VERSION 5.7 ;
  NOWIREEXTENSIONATPIN ON ;
  DIVIDERCHAR "/" ;
  BUSBITCHARS "[]" ;
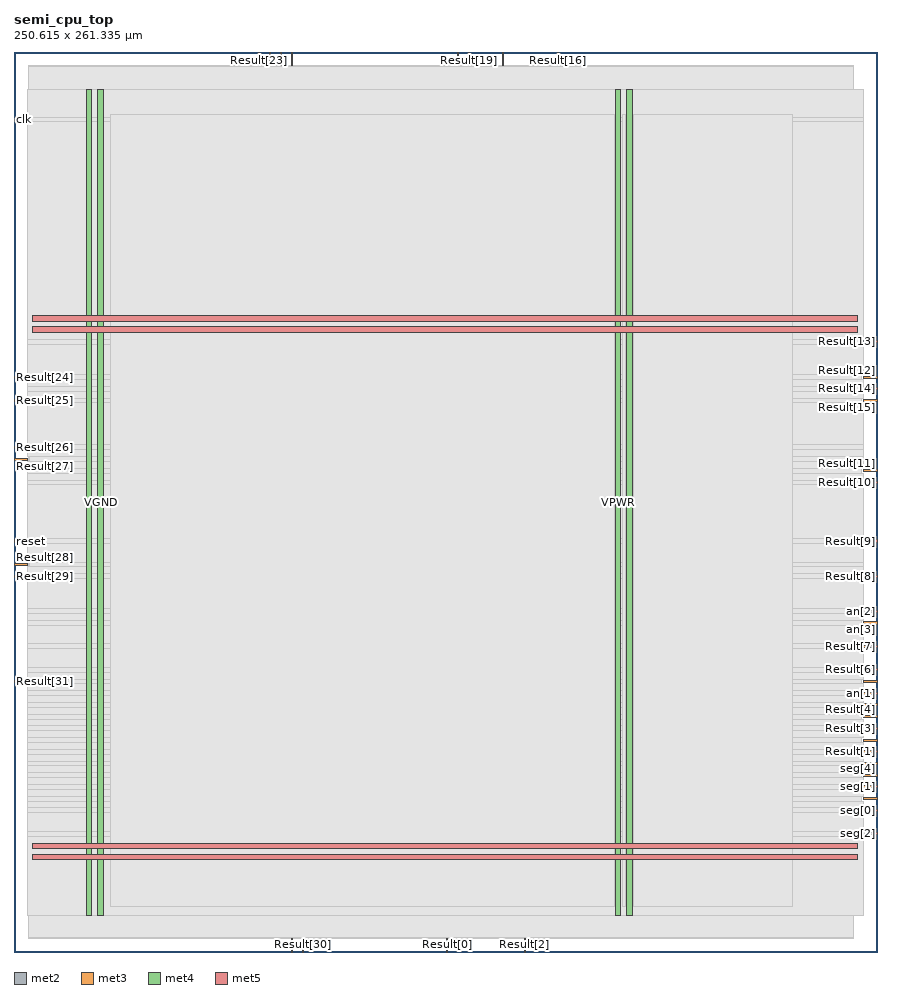
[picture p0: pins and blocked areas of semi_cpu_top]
MACRO semi_cpu_top
  CLASS BLOCK ;
  FOREIGN semi_cpu_top ;
  ORIGIN 0.000 0.000 ;
  SIZE 250.615 BY 261.335 ;
  PIN Result[0]
    DIRECTION OUTPUT ;
    USE SIGNAL ;
    ANTENNADIFFAREA 0.445500 ;
    PORT
      LAYER met2 ;
        RECT 125.670 0.000 125.950 4.000 ;
    END
  END Result[0]
  PIN Result[10]
    DIRECTION OUTPUT ;
    USE SIGNAL ;
    ANTENNADIFFAREA 0.445500 ;
    PORT
      LAYER met3 ;
        RECT 246.615 136.040 250.615 136.640 ;
    END
  END Result[10]
  PIN Result[11]
    DIRECTION OUTPUT ;
    USE SIGNAL ;
    ANTENNADIFFAREA 0.445500 ;
    PORT
      LAYER met3 ;
        RECT 246.615 139.440 250.615 140.040 ;
    END
  END Result[11]
  PIN Result[12]
    DIRECTION OUTPUT ;
    USE SIGNAL ;
    ANTENNADIFFAREA 0.445500 ;
    PORT
      LAYER met3 ;
        RECT 246.615 166.640 250.615 167.240 ;
    END
  END Result[12]
  PIN Result[13]
    DIRECTION OUTPUT ;
    USE SIGNAL ;
    ANTENNADIFFAREA 0.445500 ;
    PORT
      LAYER met3 ;
        RECT 246.615 176.840 250.615 177.440 ;
    END
  END Result[13]
  PIN Result[14]
    DIRECTION OUTPUT ;
    USE SIGNAL ;
    ANTENNADIFFAREA 0.445500 ;
    PORT
      LAYER met3 ;
        RECT 246.615 163.240 250.615 163.840 ;
    END
  END Result[14]
  PIN Result[15]
    DIRECTION OUTPUT ;
    USE SIGNAL ;
    ANTENNADIFFAREA 0.445500 ;
    PORT
      LAYER met3 ;
        RECT 246.615 159.840 250.615 160.440 ;
    END
  END Result[15]
  PIN Result[16]
    DIRECTION OUTPUT ;
    USE SIGNAL ;
    ANTENNADIFFAREA 0.795200 ;
    PORT
      LAYER met2 ;
        RECT 157.870 257.335 158.150 261.335 ;
    END
  END Result[16]
  PIN Result[17]
    DIRECTION OUTPUT ;
    USE SIGNAL ;
    ANTENNADIFFAREA 0.795200 ;
    PORT
      LAYER met2 ;
        RECT 141.770 257.335 142.050 261.335 ;
    END
  END Result[17]
  PIN Result[18]
    DIRECTION OUTPUT ;
    USE SIGNAL ;
    ANTENNADIFFAREA 0.795200 ;
    PORT
      LAYER met2 ;
        RECT 128.890 257.335 129.170 261.335 ;
    END
  END Result[18]
  PIN Result[19]
    DIRECTION OUTPUT ;
    USE SIGNAL ;
    ANTENNADIFFAREA 0.795200 ;
    PORT
      LAYER met2 ;
        RECT 132.110 257.335 132.390 261.335 ;
    END
  END Result[19]
  PIN Result[1]
    DIRECTION OUTPUT ;
    USE SIGNAL ;
    ANTENNADIFFAREA 0.445500 ;
    PORT
      LAYER met3 ;
        RECT 246.615 57.840 250.615 58.440 ;
    END
  END Result[1]
  PIN Result[20]
    DIRECTION OUTPUT ;
    USE SIGNAL ;
    ANTENNADIFFAREA 0.795200 ;
    PORT
      LAYER met2 ;
        RECT 80.590 257.335 80.870 261.335 ;
    END
  END Result[20]
  PIN Result[21]
    DIRECTION OUTPUT ;
    USE SIGNAL ;
    ANTENNADIFFAREA 0.795200 ;
    PORT
      LAYER met2 ;
        RECT 77.370 257.335 77.650 261.335 ;
    END
  END Result[21]
  PIN Result[22]
    DIRECTION OUTPUT ;
    USE SIGNAL ;
    ANTENNADIFFAREA 0.795200 ;
    PORT
      LAYER met2 ;
        RECT 74.150 257.335 74.430 261.335 ;
    END
  END Result[22]
  PIN Result[23]
    DIRECTION OUTPUT ;
    USE SIGNAL ;
    ANTENNADIFFAREA 0.795200 ;
    PORT
      LAYER met2 ;
        RECT 70.930 257.335 71.210 261.335 ;
    END
  END Result[23]
  PIN Result[24]
    DIRECTION OUTPUT ;
    USE SIGNAL ;
    ANTENNADIFFAREA 0.445500 ;
    PORT
      LAYER met3 ;
        RECT 0.000 166.640 4.000 167.240 ;
    END
  END Result[24]
  PIN Result[25]
    DIRECTION OUTPUT ;
    USE SIGNAL ;
    ANTENNADIFFAREA 0.445500 ;
    PORT
      LAYER met3 ;
        RECT 0.000 159.840 4.000 160.440 ;
    END
  END Result[25]
  PIN Result[26]
    DIRECTION OUTPUT ;
    USE SIGNAL ;
    ANTENNADIFFAREA 0.445500 ;
    PORT
      LAYER met3 ;
        RECT 0.000 146.240 4.000 146.840 ;
    END
  END Result[26]
  PIN Result[27]
    DIRECTION OUTPUT ;
    USE SIGNAL ;
    ANTENNADIFFAREA 0.445500 ;
    PORT
      LAYER met3 ;
        RECT 0.000 142.840 4.000 143.440 ;
    END
  END Result[27]
  PIN Result[28]
    DIRECTION OUTPUT ;
    USE SIGNAL ;
    ANTENNADIFFAREA 0.445500 ;
    PORT
      LAYER met3 ;
        RECT 0.000 112.240 4.000 112.840 ;
    END
  END Result[28]
  PIN Result[29]
    DIRECTION OUTPUT ;
    USE SIGNAL ;
    ANTENNADIFFAREA 1.336500 ;
    PORT
      LAYER met3 ;
        RECT 0.000 108.840 4.000 109.440 ;
    END
  END Result[29]
  PIN Result[2]
    DIRECTION OUTPUT ;
    USE SIGNAL ;
    ANTENNADIFFAREA 0.445500 ;
    PORT
      LAYER met2 ;
        RECT 148.210 0.000 148.490 4.000 ;
    END
  END Result[2]
  PIN Result[30]
    DIRECTION OUTPUT ;
    USE SIGNAL ;
    ANTENNADIFFAREA 0.795200 ;
    PORT
      LAYER met2 ;
        RECT 83.810 0.000 84.090 4.000 ;
    END
  END Result[30]
  PIN Result[31]
    DIRECTION OUTPUT ;
    USE SIGNAL ;
    ANTENNADIFFAREA 1.336500 ;
    PORT
      LAYER met3 ;
        RECT 0.000 78.240 4.000 78.840 ;
    END
  END Result[31]
  PIN Result[3]
    DIRECTION OUTPUT ;
    USE SIGNAL ;
    ANTENNADIFFAREA 0.445500 ;
    PORT
      LAYER met3 ;
        RECT 246.615 64.640 250.615 65.240 ;
    END
  END Result[3]
  PIN Result[4]
    DIRECTION OUTPUT ;
    USE SIGNAL ;
    ANTENNADIFFAREA 0.445500 ;
    PORT
      LAYER met3 ;
        RECT 246.615 68.040 250.615 68.640 ;
    END
  END Result[4]
  PIN Result[5]
    DIRECTION OUTPUT ;
    USE SIGNAL ;
    ANTENNADIFFAREA 0.445500 ;
    PORT
      LAYER met3 ;
        RECT 246.615 78.240 250.615 78.840 ;
    END
  END Result[5]
  PIN Result[6]
    DIRECTION OUTPUT ;
    USE SIGNAL ;
    ANTENNADIFFAREA 0.445500 ;
    PORT
      LAYER met3 ;
        RECT 246.615 81.640 250.615 82.240 ;
    END
  END Result[6]
  PIN Result[7]
    DIRECTION OUTPUT ;
    USE SIGNAL ;
    ANTENNADIFFAREA 0.445500 ;
    PORT
      LAYER met3 ;
        RECT 246.615 88.440 250.615 89.040 ;
    END
  END Result[7]
  PIN Result[8]
    DIRECTION OUTPUT ;
    USE SIGNAL ;
    ANTENNADIFFAREA 0.445500 ;
    PORT
      LAYER met3 ;
        RECT 246.615 108.840 250.615 109.440 ;
    END
  END Result[8]
  PIN Result[9]
    DIRECTION OUTPUT ;
    USE SIGNAL ;
    ANTENNADIFFAREA 0.445500 ;
    PORT
      LAYER met3 ;
        RECT 246.615 119.040 250.615 119.640 ;
    END
  END Result[9]
  PIN VGND
    DIRECTION INOUT ;
    USE GROUND ;
    PORT
      LAYER met4 ;
        RECT 24.340 10.640 25.940 250.480 ;
    END
    PORT
      LAYER met4 ;
        RECT 177.940 10.640 179.540 250.480 ;
    END
    PORT
      LAYER met5 ;
        RECT 5.280 30.030 244.960 31.630 ;
    END
    PORT
      LAYER met5 ;
        RECT 5.280 183.210 244.960 184.810 ;
    END
  END VGND
  PIN VPWR
    DIRECTION INOUT ;
    USE POWER ;
    PORT
      LAYER met4 ;
        RECT 21.040 10.640 22.640 250.480 ;
    END
    PORT
      LAYER met4 ;
        RECT 174.640 10.640 176.240 250.480 ;
    END
    PORT
      LAYER met5 ;
        RECT 5.280 26.730 244.960 28.330 ;
    END
    PORT
      LAYER met5 ;
        RECT 5.280 179.910 244.960 181.510 ;
    END
  END VPWR
  PIN an[0]
    DIRECTION OUTPUT ;
    USE SIGNAL ;
    ANTENNADIFFAREA 0.445500 ;
    PORT
      LAYER met3 ;
        RECT 246.615 71.440 250.615 72.040 ;
    END
  END an[0]
  PIN an[1]
    DIRECTION OUTPUT ;
    USE SIGNAL ;
    ANTENNADIFFAREA 0.445500 ;
    PORT
      LAYER met3 ;
        RECT 246.615 74.840 250.615 75.440 ;
    END
  END an[1]
  PIN an[2]
    DIRECTION OUTPUT ;
    USE SIGNAL ;
    ANTENNADIFFAREA 0.445500 ;
    PORT
      LAYER met3 ;
        RECT 246.615 98.640 250.615 99.240 ;
    END
  END an[2]
  PIN an[3]
    DIRECTION OUTPUT ;
    USE SIGNAL ;
    ANTENNADIFFAREA 0.445500 ;
    PORT
      LAYER met3 ;
        RECT 246.615 95.240 250.615 95.840 ;
    END
  END an[3]
  PIN clk
    DIRECTION INPUT ;
    USE SIGNAL ;
    ANTENNAGATEAREA 0.852000 ;
    PORT
      LAYER met3 ;
        RECT 0.000 241.440 4.000 242.040 ;
    END
  END clk
  PIN control
    DIRECTION INPUT ;
    USE SIGNAL ;
    ANTENNAGATEAREA 0.213000 ;
    PORT
      LAYER met2 ;
        RECT 80.590 0.000 80.870 4.000 ;
    END
  END control
  PIN reset
    DIRECTION INPUT ;
    USE SIGNAL ;
    ANTENNAGATEAREA 0.585000 ;
    PORT
      LAYER met3 ;
        RECT 0.000 119.040 4.000 119.640 ;
    END
  END reset
  PIN seg[0]
    DIRECTION OUTPUT ;
    USE SIGNAL ;
    ANTENNADIFFAREA 0.445500 ;
    PORT
      LAYER met3 ;
        RECT 246.615 40.840 250.615 41.440 ;
    END
  END seg[0]
  PIN seg[1]
    DIRECTION OUTPUT ;
    USE SIGNAL ;
    ANTENNADIFFAREA 0.445500 ;
    PORT
      LAYER met3 ;
        RECT 246.615 47.640 250.615 48.240 ;
    END
  END seg[1]
  PIN seg[2]
    DIRECTION OUTPUT ;
    USE SIGNAL ;
    ANTENNADIFFAREA 0.445500 ;
    PORT
      LAYER met3 ;
        RECT 246.615 34.040 250.615 34.640 ;
    END
  END seg[2]
  PIN seg[3]
    DIRECTION OUTPUT ;
    USE SIGNAL ;
    ANTENNADIFFAREA 0.445500 ;
    PORT
      LAYER met3 ;
        RECT 246.615 44.240 250.615 44.840 ;
    END
  END seg[3]
  PIN seg[4]
    DIRECTION OUTPUT ;
    USE SIGNAL ;
    ANTENNADIFFAREA 0.445500 ;
    PORT
      LAYER met3 ;
        RECT 246.615 51.040 250.615 51.640 ;
    END
  END seg[4]
  PIN seg[5]
    DIRECTION OUTPUT ;
    USE SIGNAL ;
    ANTENNADIFFAREA 0.445500 ;
    PORT
      LAYER met3 ;
        RECT 246.615 61.240 250.615 61.840 ;
    END
  END seg[5]
  PIN seg[6]
    DIRECTION OUTPUT ;
    USE SIGNAL ;
    ANTENNADIFFAREA 0.445500 ;
    PORT
      LAYER met3 ;
        RECT 246.615 54.440 250.615 55.040 ;
    END
  END seg[6]
  OBS
      LAYER nwell ;
        RECT 5.330 10.795 244.910 250.325 ;
      LAYER li1 ;
        RECT 5.520 10.795 244.720 250.325 ;
      LAYER met1 ;
        RECT 4.210 10.640 244.720 250.480 ;
      LAYER met2 ;
        RECT 4.230 257.055 70.650 257.335 ;
        RECT 71.490 257.055 73.870 257.335 ;
        RECT 74.710 257.055 77.090 257.335 ;
        RECT 77.930 257.055 80.310 257.335 ;
        RECT 81.150 257.055 128.610 257.335 ;
        RECT 129.450 257.055 131.830 257.335 ;
        RECT 132.670 257.055 141.490 257.335 ;
        RECT 142.330 257.055 157.590 257.335 ;
        RECT 158.430 257.055 243.700 257.335 ;
        RECT 4.230 4.280 243.700 257.055 ;
        RECT 4.230 4.000 80.310 4.280 ;
        RECT 81.150 4.000 83.530 4.280 ;
        RECT 84.370 4.000 125.390 4.280 ;
        RECT 126.230 4.000 147.930 4.280 ;
        RECT 148.770 4.000 243.700 4.280 ;
      LAYER met3 ;
        RECT 3.990 242.440 246.615 250.405 ;
        RECT 4.400 241.040 246.615 242.440 ;
        RECT 3.990 177.840 246.615 241.040 ;
        RECT 3.990 176.440 246.215 177.840 ;
        RECT 3.990 167.640 246.615 176.440 ;
        RECT 4.400 166.240 246.215 167.640 ;
        RECT 3.990 164.240 246.615 166.240 ;
        RECT 3.990 162.840 246.215 164.240 ;
        RECT 3.990 160.840 246.615 162.840 ;
        RECT 4.400 159.440 246.215 160.840 ;
        RECT 3.990 147.240 246.615 159.440 ;
        RECT 4.400 145.840 246.615 147.240 ;
        RECT 3.990 143.840 246.615 145.840 ;
        RECT 4.400 142.440 246.615 143.840 ;
        RECT 3.990 140.440 246.615 142.440 ;
        RECT 3.990 139.040 246.215 140.440 ;
        RECT 3.990 137.040 246.615 139.040 ;
        RECT 3.990 135.640 246.215 137.040 ;
        RECT 3.990 120.040 246.615 135.640 ;
        RECT 4.400 118.640 246.215 120.040 ;
        RECT 3.990 113.240 246.615 118.640 ;
        RECT 4.400 111.840 246.615 113.240 ;
        RECT 3.990 109.840 246.615 111.840 ;
        RECT 4.400 108.440 246.215 109.840 ;
        RECT 3.990 99.640 246.615 108.440 ;
        RECT 3.990 98.240 246.215 99.640 ;
        RECT 3.990 96.240 246.615 98.240 ;
        RECT 3.990 94.840 246.215 96.240 ;
        RECT 3.990 89.440 246.615 94.840 ;
        RECT 3.990 88.040 246.215 89.440 ;
        RECT 3.990 82.640 246.615 88.040 ;
        RECT 3.990 81.240 246.215 82.640 ;
        RECT 3.990 79.240 246.615 81.240 ;
        RECT 4.400 77.840 246.215 79.240 ;
        RECT 3.990 75.840 246.615 77.840 ;
        RECT 3.990 74.440 246.215 75.840 ;
        RECT 3.990 72.440 246.615 74.440 ;
        RECT 3.990 71.040 246.215 72.440 ;
        RECT 3.990 69.040 246.615 71.040 ;
        RECT 3.990 67.640 246.215 69.040 ;
        RECT 3.990 65.640 246.615 67.640 ;
        RECT 3.990 64.240 246.215 65.640 ;
        RECT 3.990 62.240 246.615 64.240 ;
        RECT 3.990 60.840 246.215 62.240 ;
        RECT 3.990 58.840 246.615 60.840 ;
        RECT 3.990 57.440 246.215 58.840 ;
        RECT 3.990 55.440 246.615 57.440 ;
        RECT 3.990 54.040 246.215 55.440 ;
        RECT 3.990 52.040 246.615 54.040 ;
        RECT 3.990 50.640 246.215 52.040 ;
        RECT 3.990 48.640 246.615 50.640 ;
        RECT 3.990 47.240 246.215 48.640 ;
        RECT 3.990 45.240 246.615 47.240 ;
        RECT 3.990 43.840 246.215 45.240 ;
        RECT 3.990 41.840 246.615 43.840 ;
        RECT 3.990 40.440 246.215 41.840 ;
        RECT 3.990 35.040 246.615 40.440 ;
        RECT 3.990 33.640 246.215 35.040 ;
        RECT 3.990 10.715 246.615 33.640 ;
      LAYER met4 ;
        RECT 27.895 13.095 174.240 243.265 ;
        RECT 176.640 13.095 177.540 243.265 ;
        RECT 179.940 13.095 226.025 243.265 ;
  END
END semi_cpu_top
END LIBRARY

